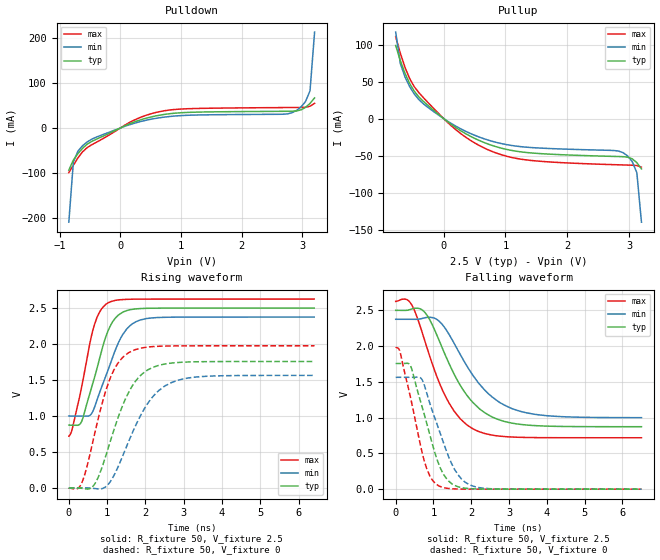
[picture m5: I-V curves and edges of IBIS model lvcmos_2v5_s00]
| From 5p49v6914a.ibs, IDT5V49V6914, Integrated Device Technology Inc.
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|   Model LVCMOS_2V5
[Model]   lvcmos_2v5_s00
Model_type   Output
Polarity   Non-Inverting
|   typ   min   max
C_comp   2pF   1.5pF   2.5pF
Vmeas = 1.25V
Rref = 50
Cref = 0
Vref = 1.25V
|   typ   min   max
[Voltage range]   2.5V   2.375V   2.625V
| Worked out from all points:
|   slope of the pulldown table from 0 to 0.375 V, typ, clamps not added: 18.9 ohm
|   slope of the pullup table from 0 to 0.375 V, typ, clamps not added: 17.6 ohm
|   rising waveform, R_fixture 50, V_fixture 2.5: 20-80 % time 531ps typ, 605ps min, 446ps max; typ from 0.873 V to 2.5 V
|   falling waveform, R_fixture 50, V_fixture 2.5: 20-80 % time 998ps typ, 1.11ns min, 867ps max; typ from 2.5 V to 0.873 V
|   rising waveform, R_fixture 50, V_fixture 0: 20-80 % time 736ps typ, 865ps min, 606ps max; typ from 0 V to 1.76 V
|   falling waveform, R_fixture 50, V_fixture 0: 20-80 % time 579ps typ, 649ps min, 498ps max; typ from 1.76 V to 0 V
[Pulldown]
|Voltage   I (typ)   I (min)   I (max)
|Note, modeling breaks down at 250mA and above.  This is well beyond the functional   |
|operating range of the device.  Should this scenario occur, catastrophic failure and   |
|possible damage to the device and/or board is of higher concern than the I-V curve   |
|behavior.  The IBIS checker will flag currents in excess of 10A with warnings.  Lines   |
|with currents in excess of 0.35 A have been commented out.  The points still remain|
|available to the user if the user desires to use them.   |
|-2.50000e+00   -2.65608e+02   -2.29941e+02   -3.26165e+02
|-2.42500e+00   -2.52343e+02   -2.18875e+02   -3.09252e+02
|-2.35000e+00   -2.39080e+02   -2.07811e+02   -2.92340e+02
|-2.27500e+00   -2.25818e+02   -1.96747e+02   -2.75428e+02
|-2.20000e+00   -2.12557e+02   -1.85685e+02   -2.58518e+02
|-2.12500e+00   -1.99297e+02   -1.74624e+02   -2.41608e+02
|-2.05000e+00   -1.86039e+02   -1.63565e+02   -2.24700e+02
|-1.97500e+00   -1.72782e+02   -1.52508e+02   -2.07793e+02
|-1.90000e+00   -1.59528e+02   -1.41453e+02   -1.90888e+02
|-1.82500e+00   -1.46276e+02   -1.30401e+02   -1.73985e+02
|-1.75000e+00   -1.33027e+02   -1.19352e+02   -1.57085e+02
|-1.67500e+00   -1.19782e+02   -1.08307e+02   -1.40188e+02
|-1.60000e+00   -1.06542e+02   -9.72682e+01   -1.23295e+02
|-1.52500e+00   -9.33090e+01   -8.62359e+01   -1.06409e+02
|-1.45000e+00   -8.00850e+01   -7.52129e+01   -8.95309e+01
|-1.37500e+00   -6.68743e+01   -6.42029e+01   -7.26657e+01
|-1.30000e+00   -5.36897e+01   -5.32178e+01   -5.58258e+01
|-1.22500e+00   -4.05463e+01   -4.22664e+01   -3.90371e+01
|-1.15000e+00   -2.74527e+01   -3.13543e+01   -2.23159e+01
|-1.07500e+00   -1.44175e+01   -2.04874e+01   -5.67477e+00
|-1.00000e+00   -2.41445e+00   -9.65733e+00   -2.99544e-01
|-9.25000e-01   -2.45532e-01   -1.42571e+00   -1.20411e-01
-850mV    -93.99mA   -210mA     -99.45mA
-775mV    -71.55mA   -76.14mA   -83.12mA
-700mV    -57.23mA   -51.66mA   -66.79mA
-550mV    -36.49mA   -31.4mA    -44.03mA
200mV     11.86mA    9.308mA    15.7mA
650mV     28.48mA    22.79mA    36.43mA
1.175V    34.92mA    28.53mA    43.11mA
2.825V    37.25mA    33.68mA    45.54mA
2.975V    40.25mA    46.76mA    45.71mA
3.05V     45.87mA    58.57mA    46.09mA
3.125V    54.76mA    82.96mA    48.46mA
3.2V      67.01mA    213.6mA    54.81mA
| 3.27500e+00   8.22893e-02   1.48202e+00   6.52461e-02
| 3.35000e+00   1.11691e-01   1.21021e+01   7.95740e-02
| 3.42500e+00   4.17187e-01   2.91692e+01   9.49987e-02
| 3.50000e+00   5.44922e+00   4.62676e+01   1.08609e-01
| 3.57500e+00   2.52763e+01   6.34104e+01   1.52479e-01
| 3.65000e+00   4.58138e+01   8.05959e+01   1.32846e+00
| 3.72500e+00   6.64097e+01   9.78129e+01   2.01980e+01
| 3.80000e+00   8.70553e+01   1.15052e+02   4.64595e+01
| 3.87500e+00   1.07734e+02   1.32307e+02   7.28003e+01
| 3.95000e+00   1.28434e+02   1.49572e+02   9.91974e+01
| 4.02500e+00   1.49148e+02   1.66846e+02   1.25626e+02
| 4.10000e+00   1.69871e+02   1.84125e+02   1.52073e+02
| 4.17500e+00   1.90602e+02   2.01410e+02   1.78532e+02
| 4.25000e+00   2.11338e+02   2.18698e+02   2.05000e+02
| 4.32500e+00   2.32079e+02   2.35990e+02   2.31473e+02
| 4.40000e+00   2.52823e+02   2.53284e+02   2.57951e+02
| 4.47500e+00   2.73570e+02   2.70581e+02   2.84433e+02
| 4.55000e+00   2.94320e+02   2.87880e+02   3.10918e+02
| 4.62500e+00   3.15072e+02   3.05181e+02   3.37405e+02
| 4.70000e+00   3.35826e+02   3.22484e+02   3.63895e+02
| 4.77500e+00   3.56582e+02   3.39789e+02   3.90387e+02
| 4.85000e+00   3.77340e+02   3.57095e+02   4.16881e+02
| 4.92500e+00   3.98099e+02   3.74402e+02   4.43377e+02
| 5.00000e+00   4.18860e+02   3.91711e+02   4.69874e+02
[Pullup]
|Voltage   I (typ)   I (min)   I (max)
|Note, modeling breaks down at 250mA and above.  This is well beyond the functional   |
|operating range of the device.  Should this scenario occur, catastrophic failure and   |
|possible damage to the device and/or board is of higher concern than the I-V curve   |
|behavior.  The IBIS checker will flag currents in excess of 10A with warnings.  Lines   |
|with currents in excess of 0.35 A have been commented out.  The points still remain|
|available to the user if the user desires to use them.   |
|-2.50000e+00   4.18924e+02   3.62922e+02   5.14110e+02
|-2.42500e+00   3.98163e+02   3.45615e+02   4.87611e+02
|-2.35000e+00   3.77403e+02   3.28309e+02   4.61112e+02
|-2.27500e+00   3.56644e+02   3.11005e+02   4.34615e+02
|-2.20000e+00   3.35887e+02   2.93702e+02   4.08119e+02
|-2.12500e+00   3.15132e+02   2.76401e+02   3.81625e+02
|-2.05000e+00   2.94379e+02   2.59102e+02   3.55132e+02
|-1.97500e+00   2.73627e+02   2.41805e+02   3.28642e+02
|-1.90000e+00   2.52879e+02   2.24511e+02   3.02154e+02
|-1.82500e+00   2.32133e+02   2.07220e+02   2.75668e+02
|-1.75000e+00   2.11391e+02   1.89933e+02   2.49186e+02
|-1.67500e+00   1.90653e+02   1.72650e+02   2.22708e+02
|-1.60000e+00   1.69920e+02   1.55373e+02   1.96234e+02
|-1.52500e+00   1.49194e+02   1.38102e+02   1.69767e+02
|-1.45000e+00   1.28478e+02   1.20842e+02   1.43309e+02
|-1.37500e+00   1.07776e+02   1.03595e+02   1.16864e+02
|-1.30000e+00   8.70950e+01   8.63670e+01   9.04416e+01
|-1.22500e+00   6.64470e+01   6.91675e+01   6.40570e+01
|-1.15000e+00   4.58485e+01   5.20071e+01   3.77381e+01
|-1.07500e+00   2.53080e+01   3.48921e+01   1.14975e+01
|-1.00000e+00   5.47770e+00   1.78138e+01   5.20511e-01
|-9.25000e-01   4.42241e-01   3.17254e+00   1.56153e-01
|-8.50000e-01   1.32908e-01   3.92497e-01   1.29698e-01
-775mV    98.68mA    116.8mA    110.3mA
-700mV    78.11mA    74.31mA    88.11mA
-625mV    61.11mA    56.31mA    69.18mA
-475mV    36.93mA    33.22mA    43.05mA
-325mV    23.07mA    19.8mA     28.08mA
125mV     -7.951mA   -6.687mA   -9.848mA
575mV     -29.56mA   -24.95mA   -36.3mA
1.325V    -45.7mA    -38.54mA   -55.7mA
2.9V      -51.46mA   -45.91mA   -62.61mA
3.05V     -54.28mA   -57.96mA   -62.98mA
3.125V    -59.49mA   -72.96mA   -63.43mA
3.2V      -67.99mA   -139.9mA   -65.6mA
| 3.27500e+00   -7.95179e-02   -7.11252e-01   -7.19088e-02
| 3.35000e+00   -9.96915e-02   -6.05603e+00   -8.27613e-02
| 3.42500e+00   -2.49209e-01   -1.68766e+01   -9.65190e-02
| 3.50000e+00   -2.41654e+00   -2.77285e+01   -1.10622e-01
| 3.57500e+00   -1.44189e+01   -3.86247e+01   -1.40364e-01
| 3.65000e+00   -2.74535e+01   -4.95634e+01   -6.78328e-01
| 3.72500e+00   -4.05466e+01   -6.05360e+01   -1.12141e+01
| 3.80000e+00   -5.36896e+01   -7.15395e+01   -2.78806e+01
| 3.87500e+00   -6.68736e+01   -8.25581e+01   -4.46279e+01
| 3.95000e+00   -8.00835e+01   -9.35871e+01   -6.14343e+01
| 4.02500e+00   -9.33072e+01   -1.04624e+02   -7.82862e+01
| 4.10000e+00   -1.06540e+02   -1.15666e+02   -9.51560e+01
| 4.17500e+00   -1.19780e+02   -1.26714e+02   -1.12037e+02
| 4.25000e+00   -1.33024e+02   -1.37764e+02   -1.28926e+02
| 4.32500e+00   -1.46273e+02   -1.48818e+02   -1.45820e+02
| 4.40000e+00   -1.59525e+02   -1.59874e+02   -1.62718e+02
| 4.47500e+00   -1.72779e+02   -1.70933e+02   -1.79619e+02
| 4.55000e+00   -1.86036e+02   -1.81993e+02   -1.96523e+02
| 4.62500e+00   -1.99294e+02   -1.93055e+02   -2.13429e+02
| 4.70000e+00   -2.12554e+02   -2.04118e+02   -2.30337e+02
| 4.77500e+00   -2.25816e+02   -2.15182e+02   -2.47246e+02
| 4.85000e+00   -2.39078e+02   -2.26248e+02   -2.64156e+02
| 4.92500e+00   -2.52342e+02   -2.37314e+02   -2.81068e+02
| 5.00000e+00   -2.65606e+02   -2.48382e+02   -2.97980e+02
[Ramp]
|   typ   min   max
dV/dt_r   1.063/0.739n   0.946/0.869n   1.195/0.609n
dV/dt_f   0.994/1.005n   0.841/1.117n   1.163/0.875n
R_load =   50
[Rising Waveform]
R_fixture = 50
V_fixture = 2.5   |Vcc_typ
V_fixture_min = 2.375 |Vcc_min
V_fixture_max = 2.625 |Vcc_max
C_fixture = 0.0p
| Time   typ   min   max
| 0.00000e+00   8.73021e-01   9.99328e-01   7.18803e-01
| 2.82958e-12   8.73021e-01   9.99328e-01   7.18803e-01
| 5.01945e-12   8.73021e-01   9.99328e-01   7.18803e-01
| 5.29250e-12   8.73021e-01   9.99328e-01   7.18803e-01
| 8.83938e-12   8.73021e-01   9.99328e-01   7.18803e-01
| 1.58159e-11   8.73021e-01   9.99328e-01   7.18803e-01
| 1.65816e-11   8.73021e-01   9.99328e-01   7.18803e-01
| 3.09307e-11   8.73021e-01   9.99328e-01   7.18803e-01
| 4.33456e-11   8.73021e-01   9.99328e-01   7.18803e-01
| 4.84997e-11   8.73021e-01   9.99328e-01   7.18803e-01
| 5.92498e-11   8.73021e-01   9.99328e-01   7.18803e-01
| 6.33903e-11   8.73021e-01   9.99328e-01   7.18803e-01
| 7.24942e-11   8.73021e-01   9.99328e-01   7.18803e-01
| 7.37142e-11   8.73021e-01   9.99328e-01   7.18803e-01
| 7.72112e-11   8.73021e-01   9.99328e-01   7.18803e-01
| 8.08094e-11   8.73021e-01   9.99328e-01   7.18803e-01
| 8.33740e-11   8.73021e-01   9.99328e-01   7.18803e-01
| 8.93880e-11   8.73021e-01   9.99328e-01   7.18803e-01
| 1.00166e-10   8.73021e-01   9.99328e-01   7.18804e-01
| 1.04900e-10   8.73021e-01   9.99328e-01   7.18804e-01
| 1.14234e-10   8.73022e-01   9.99328e-01   7.18804e-01
| 1.18465e-10   8.73022e-01   9.99329e-01   7.18804e-01
| 1.25023e-10   8.73022e-01   9.99329e-01   7.18804e-01
| 1.37358e-10   8.73022e-01   9.99329e-01   7.18804e-01
| 1.40589e-10   8.73022e-01   9.99329e-01   7.18804e-01
| 1.51767e-10   8.73021e-01   9.99328e-01   7.18802e-01
| 1.61060e-10   8.73019e-01   9.99327e-01   7.18800e-01
| 1.69091e-10   8.73016e-01   9.99324e-01   7.18798e-01
| 1.80923e-10   8.73012e-01   9.99320e-01   7.18792e-01
| 1.98540e-10   8.73004e-01   9.99312e-01   7.18784e-01
| 2.03752e-10   8.73002e-01   9.99309e-01   7.18782e-01
| 2.22970e-10   8.72994e-01   9.99302e-01   7.18775e-01
| 2.39229e-10   8.72989e-01   9.99298e-01   7.18772e-01
| 2.45359e-10   8.72988e-01   9.99296e-01   7.18773e-01
| 2.53236e-10   8.72988e-01   9.99294e-01   7.18776e-01
| 2.61834e-10   8.72990e-01   9.99294e-01   7.18782e-01
| 2.68845e-10   8.72994e-01   9.99295e-01   7.18785e-01
| 2.75097e-10   8.72996e-01   9.99297e-01   7.18788e-01
| 2.84408e-10   8.73000e-01   9.99300e-01   7.18791e-01
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0s        873mV      999.3mV    718.8mV
82.27ps   872.4mV    998.8mV    805.2mV
342.9ps   934.1mV    998.5mV    1.423V
544.2ps   1.3V       1.006V     1.997V
666.1ps   1.523V     1.114V     2.265V
845.8ps   1.89V      1.387V     2.481V
1.024ns   2.183V     1.637V     2.572V
1.422ns   2.447V     2.143V     2.619V
1.873ns   2.493V     2.336V     2.624V
6.407ns   2.5V       2.375V     2.625V
[Falling Waveform]
R_fixture = 50
V_fixture = 2.5   |Vcc_typ
V_fixture_min = 2.375 |Vcc_min
V_fixture_max = 2.625 |Vcc_max
C_fixture = 0.0p
| Time   typ   min   max
| 0.00000e+00   2.50000e+00   2.37500e+00   2.62500e+00
| 2.82958e-12   2.50000e+00   2.37500e+00   2.62500e+00
| 5.01945e-12   2.50000e+00   2.37500e+00   2.62500e+00
| 5.29250e-12   2.50000e+00   2.37500e+00   2.62500e+00
| 8.83938e-12   2.50000e+00   2.37500e+00   2.62500e+00
| 1.58159e-11   2.50000e+00   2.37500e+00   2.62500e+00
| 1.65816e-11   2.50000e+00   2.37500e+00   2.62500e+00
| 3.09306e-11   2.50000e+00   2.37500e+00   2.62500e+00
| 4.33456e-11   2.50000e+00   2.37500e+00   2.62500e+00
| 4.84997e-11   2.50000e+00   2.37500e+00   2.62500e+00
| 5.92499e-11   2.50000e+00   2.37500e+00   2.62500e+00
| 6.33904e-11   2.50000e+00   2.37500e+00   2.62500e+00
| 7.24942e-11   2.50000e+00   2.37500e+00   2.62500e+00
| 7.37143e-11   2.50000e+00   2.37500e+00   2.62500e+00
| 7.72112e-11   2.50000e+00   2.37500e+00   2.62500e+00
| 8.08094e-11   2.50000e+00   2.37500e+00   2.62500e+00
| 8.33740e-11   2.50000e+00   2.37500e+00   2.62500e+00
| 8.93881e-11   2.50000e+00   2.37500e+00   2.62500e+00
| 1.00162e-10   2.50000e+00   2.37500e+00   2.62500e+00
| 1.04901e-10   2.50000e+00   2.37500e+00   2.62500e+00
| 1.14235e-10   2.50000e+00   2.37500e+00   2.62500e+00
| 1.18460e-10   2.50000e+00   2.37500e+00   2.62500e+00
| 1.25023e-10   2.50000e+00   2.37500e+00   2.62500e+00
| 1.37358e-10   2.50000e+00   2.37500e+00   2.62500e+00
| 1.40585e-10   2.50000e+00   2.37500e+00   2.62500e+00
| 1.51766e-10   2.50000e+00   2.37500e+00   2.62500e+00
| 1.61057e-10   2.50000e+00   2.37500e+00   2.62500e+00
| 1.69080e-10   2.50000e+00   2.37500e+00   2.62500e+00
| 1.80919e-10   2.49999e+00   2.37500e+00   2.62499e+00
| 1.99499e-10   2.49999e+00   2.37499e+00   2.62499e+00
| 2.05003e-10   2.49999e+00   2.37499e+00   2.62499e+00
| 2.24273e-10   2.49998e+00   2.37498e+00   2.62498e+00
| 2.39981e-10   2.49998e+00   2.37498e+00   2.62498e+00
| 2.47898e-10   2.49998e+00   2.37498e+00   2.62498e+00
| 2.62665e-10   2.49998e+00   2.37498e+00   2.62499e+00
| 2.73527e-10   2.49998e+00   2.37498e+00   2.62499e+00
| 2.79768e-10   2.49998e+00   2.37498e+00   2.62499e+00
| 2.89155e-10   2.49999e+00   2.37498e+00   2.62500e+00
| 2.95491e-10   2.49999e+00   2.37498e+00   2.62500e+00
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0s        2.5V       2.375V     2.625V
395.8ps   2.514V     2.375V     2.6V
795.8ps   2.456V     2.399V     2.032V
1.089ns   2.156V     2.373V     1.576V
1.36ns    1.819V     2.21V      1.255V
1.71ns    1.452V     1.882V     983.5mV
2.042ns   1.213V     1.592V     844.6mV
2.67ns    983.2mV    1.243V     746.4mV
3.397ns   900.4mV    1.075V     723.5mV
6.508ns   873.1mV    999.8mV    718.8mV
[Rising Waveform]
R_fixture = 50
V_fixture = 0
C_fixture = 0.0p
| Time   typ   min   max
| 0.00000e+00   6.87937e-09   4.94005e-08   5.62352e-09
| 2.82958e-12   9.39157e-09   5.18209e-08   8.20033e-09
| 5.01945e-12   1.05581e-08   5.29931e-08   9.33987e-09
| 5.29250e-12   1.06628e-08   5.30634e-08   9.47845e-09
| 8.83938e-12   1.14816e-08   5.39073e-08   1.01769e-08
| 1.58159e-11   9.81130e-09   5.35175e-08   7.82962e-09
| 1.65816e-11   9.85627e-09   5.39615e-08   7.55894e-09
| 3.09307e-11   1.50764e-08   6.38826e-08   9.11087e-09
| 4.33456e-11   5.21545e-08   9.87199e-08   4.07320e-08
| 4.84997e-11   6.75477e-08   1.14275e-07   5.79639e-08
| 5.92498e-11   1.01130e-07   1.49632e-07   9.24943e-08
| 6.33903e-11   1.01692e-07   1.48315e-07   1.03972e-07
| 7.24942e-11   7.31924e-08   1.02828e-07   9.86609e-08
| 7.37142e-11   5.88126e-08   7.73980e-08   9.03629e-08
| 7.72112e-11   -3.95219e-09   4.51221e-09   5.75014e-08
| 8.08094e-11   -7.54585e-08   -9.72558e-08   1.82286e-08
| 8.33740e-11   -1.30114e-07   -1.50261e-07   1.63174e-08
| 8.93880e-11   -1.48483e-07   -2.64533e-07   4.55777e-08
| 1.00166e-10   1.24715e-07   -4.27491e-08   3.34632e-07
| 1.04900e-10   3.02299e-07   1.49095e-07   5.73652e-07
| 1.14234e-10   9.38485e-07   7.75461e-07   9.82572e-07
| 1.18465e-10   1.16758e-06   1.08592e-06   1.13983e-06
| 1.25023e-10   1.50679e-06   1.56707e-06   1.16138e-06
| 1.37358e-10   1.64374e-06   1.93927e-06   9.99399e-07
| 1.40589e-10   1.48316e-06   1.94748e-06   9.02992e-07
| 1.51767e-10   5.02520e-07   1.34338e-06   -1.50975e-07
| 1.61060e-10   -1.03282e-06   -4.02985e-07   -2.43195e-06
| 1.69091e-10   -3.75918e-06   -2.59629e-06   -4.52065e-06
| 1.80923e-10   -7.88718e-06   -6.71275e-06   -9.21064e-06
| 1.98540e-10   -1.48427e-05   -1.37498e-05   -1.59177e-05
| 2.03752e-10   -1.65377e-05   -1.57906e-05   -1.78603e-05
| 2.22970e-10   -2.24928e-05   -2.19505e-05   -2.34608e-05
| 2.39229e-10   -2.68321e-05   -2.61824e-05   -2.48124e-05
| 2.45360e-10   -2.73651e-05   -2.77472e-05   -2.41019e-05
| 2.53236e-10   -2.75026e-05   -2.88967e-05   -2.07341e-05
| 2.61834e-10   -2.50357e-05   -2.91170e-05   -1.50696e-05
| 2.68845e-10   -2.15683e-05   -2.81518e-05   -1.16260e-05
| 2.75097e-10   -1.87100e-05   -2.59378e-05   -8.92132e-06
| 2.84408e-10   -1.47909e-05   -2.25686e-05   -6.60182e-06
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0s        6.879nV    49.4nV     5.624nV
326.9ps   -4.667mV   42.68uV    58.16mV
451ps     -13.96mV   247.1uV    251.9mV
697.3ps   72.84mV    -9.194mV   804.8mV
1.091ns   660.8mV    93.36mV    1.538V
1.555ns   1.32V      637.5mV    1.878V
1.804ns   1.525V     934.4mV    1.932V
2.135ns   1.66V      1.23V      1.962V
2.805ns   1.742V     1.49V      1.974V
6.417ns   1.757V     1.564V     1.975V
[Falling Waveform]
R_fixture = 50
V_fixture = 0
C_fixture = 0.0p
| Time   typ   min   max
| 0.00000e+00   1.75700e+00   1.56389e+00   1.97545e+00
| 1.99499e-10   1.75699e+00   1.56388e+00   1.97544e+00
| 2.24273e-10   1.75698e+00   1.56387e+00   1.97543e+00
| 2.63808e-10   1.75697e+00   1.56386e+00   1.97543e+00
| 3.01812e-10   1.75699e+00   1.56387e+00   1.97544e+00
| 3.86470e-10   1.75699e+00   1.56388e+00   1.97545e+00
| 4.27401e-10   1.75700e+00   1.56389e+00   1.97545e+00
| 7.14375e-10   1.75700e+00   1.56390e+00   1.97546e+00
| 7.53456e-10   1.75700e+00   1.56389e+00   1.97545e+00
| 8.44628e-10   1.75700e+00   1.56390e+00   1.97544e+00
| 9.56627e-10   1.75699e+00   1.56390e+00   1.97546e+00
| 9.95333e-10   1.75699e+00   1.56389e+00   1.97547e+00
| 1.07228e-09   1.75700e+00   1.56389e+00   1.97546e+00
| 1.12623e-09   1.75701e+00   1.56388e+00   1.97545e+00
| 1.18162e-09   1.75701e+00   1.56389e+00   1.97546e+00
| 1.29679e-09   1.75701e+00   1.56390e+00   1.97546e+00
| 1.37555e-09   1.75701e+00   1.56391e+00   1.97540e+00
| 1.41895e-09   1.75702e+00   1.56391e+00   1.97544e+00
| 1.42811e-09   1.75702e+00   1.56391e+00   1.97552e+00
| 1.44671e-09   1.75702e+00   1.56391e+00   1.97573e+00
| 1.46338e-09   1.75702e+00   1.56390e+00   1.97610e+00
| 1.47276e-09   1.75702e+00   1.56390e+00   1.97648e+00
| 1.48171e-09   1.75702e+00   1.56390e+00   1.97697e+00
| 1.49743e-09   1.75702e+00   1.56390e+00   1.97793e+00
| 1.51410e-09   1.75702e+00   1.56390e+00   1.97845e+00
| 1.51950e-09   1.75702e+00   1.56390e+00   1.97831e+00
| 1.53374e-09   1.75702e+00   1.56390e+00   1.97724e+00
| 1.55213e-09   1.75702e+00   1.56391e+00   1.97282e+00
| 1.56326e-09   1.75701e+00   1.56391e+00   1.96771e+00
| 1.57738e-09   1.75700e+00   1.56391e+00   1.95713e+00
| 1.59292e-09   1.75700e+00   1.56391e+00   1.93956e+00
| 1.61891e-09   1.75696e+00   1.56391e+00   1.89448e+00
| 1.63285e-09   1.75695e+00   1.56392e+00   1.86313e+00
| 1.64656e-09   1.75694e+00   1.56392e+00   1.83057e+00
| 1.66868e-09   1.75698e+00   1.56392e+00   1.77586e+00
| 1.68649e-09   1.75707e+00   1.56392e+00   1.73119e+00
| 1.69224e-09   1.75710e+00   1.56392e+00   1.71706e+00
| 1.70422e-09   1.75723e+00   1.56393e+00   1.68774e+00
| 1.71967e-09   1.75747e+00   1.56393e+00   1.65142e+00
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0s        1.757V     1.564V     1.975V
127.2ps   1.757V     1.564V     1.894V
391.3ps   1.726V     1.564V     1.284V
673.6ps   1.198V     1.549V     572.5mV
824.6ps   915.2mV    1.339V     281.6mV
1.139ns   352.6mV    840.8mV    47.09mV
1.354ns   143.2mV    519.5mV    12.94mV
1.564ns   51.38mV    271.5mV    3.901mV
2.032ns   5.223mV    45.24mV    235.9uV
6.508ns   -2.166uV   -2.579uV   -1.571uV
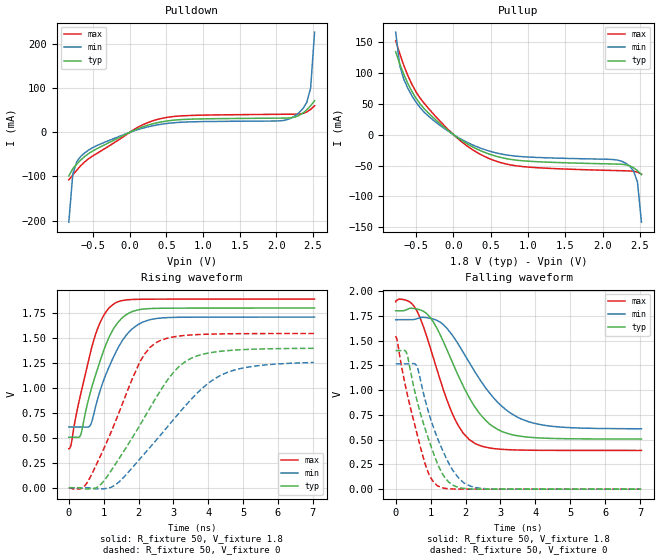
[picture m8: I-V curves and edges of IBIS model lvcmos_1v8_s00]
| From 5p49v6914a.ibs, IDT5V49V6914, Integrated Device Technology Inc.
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|   Model LVCMOS_1V8
[Model]   lvcmos_1v8_s00
Model_type   Output
Polarity   Non-Inverting
|   typ   min   max
C_comp   2pF   1.5pF   2.5pF
Vmeas = 0.9V
Rref = 50
Cref = 0
Vref = 0.9V
|   typ   min   max
[Voltage range]   1.8V   1.71V   1.89V
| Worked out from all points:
|   slope of the pulldown table from 0 to 0.27 V, typ, clamps not added: 15.4 ohm
|   slope of the pullup table from 0 to 0.27 V, typ, clamps not added: 13.1 ohm
|   rising waveform, R_fixture 50, V_fixture 1.8: 20-80 % time 719ps typ, 787ps min, 632ps max; typ from 0.506 V to 1.8 V
|   falling waveform, R_fixture 50, V_fixture 1.8: 20-80 % time 1.1ns typ, 1.32ns min, 875ps max; typ from 1.8 V to 0.506 V
|   rising waveform, R_fixture 50, V_fixture 0: 20-80 % time 1.5ns typ, 1.91ns min, 1.11ns max; typ from 0 V to 1.4 V
|   falling waveform, R_fixture 50, V_fixture 0: 20-80 % time 708ps typ, 767ps min, 628ps max; typ from 1.4 V to 0 V
[Pulldown]
|Voltage   I (typ)   I (min)   I (max)
|Note, modeling breaks down at 250mA and above.  This is well beyond the functional   |
|operating range of the device.  Should this scenario occur, catastrophic failure and   |
|possible damage to the device and/or board is of higher concern than the I-V curve   |
|behavior.  The IBIS checker will flag currents in excess of 10A with warnings.  Lines   |
|with currents in excess of 0.35 A have been commented out.  The points still remain|
|available to the user if the user desires to use them.   |
|-1.80000e+00   -1.57123e+02   -1.41687e+02   -1.84032e+02
|-1.74600e+00   -1.46350e+02   -1.32525e+02   -1.70600e+02
|-1.69200e+00   -1.35593e+02   -1.23381e+02   -1.57181e+02
|-1.63800e+00   -1.24855e+02   -1.14259e+02   -1.43777e+02
|-1.58400e+00   -1.14140e+02   -1.05164e+02   -1.30391e+02
|-1.53000e+00   -1.03454e+02   -9.61014e+01   -1.17030e+02
|-1.47600e+00   -9.28051e+01   -8.70803e+01   -1.03700e+02
|-1.42200e+00   -8.22059e+01   -7.81126e+01   -9.04125e+01
|-1.36800e+00   -7.16734e+01   -6.92147e+01   -7.71843e+01
|-1.31400e+00   -6.12369e+01   -6.04138e+01   -6.40446e+01
|-1.26000e+00   -5.09378e+01   -5.17410e+01   -5.10499e+01
|-1.20600e+00   -4.08235e+01   -4.32303e+01   -3.82636e+01
|-1.15200e+00   -3.09387e+01   -3.49134e+01   -2.57664e+01
|-1.09800e+00   -2.12858e+01   -2.67907e+01   -1.35591e+01
|-1.04400e+00   -1.18008e+01   -1.88242e+01   -2.48786e+00
|-9.90000e-01   -2.94592e+00   -1.09564e+01   -3.30913e-01
|-9.36000e-01   -5.04093e-01   -3.41190e+00   -1.45436e-01
|-8.82000e-01   -1.55884e-01   -7.28672e-01   -1.19691e-01
-828mV    -98.74mA   -203.8mA   -107.8mA
-774mV    -82.54mA   -94.98mA   -96.94mA
-720mV    -71.89mA   -66.58mA   -85.84mA
-612mV    -54.71mA   -46.44mA   -66.79mA
-450mV    -37.4mA    -30.21mA   -48.14mA
144mV     10.52mA    8.041mA    14.45mA
468mV     24.92mA    19.47mA    32.9mA
2.034V    32.4mA     26.18mA    41.13mA
2.304V    38.17mA    44.17mA    41.74mA
2.412V    50.97mA    67.63mA    46.33mA
2.466V    60.46mA    100.4mA    52.18mA
2.52V     72.02mA    227.8mA    60.53mA
| 2.57400e+00   8.57382e-02   8.78094e-01   7.13755e-02
| 2.62800e+00   1.08415e-01   4.40618e+00   8.43612e-02
| 2.68200e+00   2.11755e-01   1.54961e+01   9.74736e-02
| 2.73600e+00   9.45213e-01   2.77829e+01   1.08890e-01
| 2.79000e+00   6.44762e+00   4.00829e+01   1.24073e-01
| 2.84400e+00   2.08796e+01   5.24028e+01   1.97645e-01
| 2.89800e+00   3.56490e+01   6.47465e+01   1.06236e+00
| 2.95200e+00   5.04441e+01   7.71133e+01   1.09978e+01
| 3.00600e+00   6.52701e+01   8.94994e+01   2.98762e+01
| 3.06000e+00   8.01244e+01   1.01900e+02   4.87902e+01
| 3.11400e+00   9.50001e+01   1.14313e+02   6.77471e+01
| 3.16800e+00   1.09892e+02   1.26734e+02   8.67385e+01
| 3.22200e+00   1.24795e+02   1.39162e+02   1.05753e+02
| 3.27600e+00   1.39706e+02   1.51595e+02   1.24783e+02
| 3.33000e+00   1.54624e+02   1.64032e+02   1.43824e+02
| 3.38400e+00   1.69547e+02   1.76473e+02   1.62872e+02
| 3.43800e+00   1.84473e+02   1.88917e+02   1.81926e+02
| 3.49200e+00   1.99403e+02   2.01364e+02   2.00984e+02
| 3.54600e+00   2.14336e+02   2.13813e+02   2.20045e+02
| 3.60000e+00   2.29271e+02   2.26263e+02   2.39110e+02
[Pullup]
|Voltage   I (typ)   I (min)   I (max)
|Note, modeling breaks down at 250mA and above.  This is well beyond the functional   |
|operating range of the device.  Should this scenario occur, catastrophic failure and   |
|possible damage to the device and/or board is of higher concern than the I-V curve   |
|behavior.  The IBIS checker will flag currents in excess of 10A with warnings.  Lines   |
|with currents in excess of 0.35 A have been commented out.  The points still remain|
|available to the user if the user desires to use them.   |
|-1.80000e+00   2.29375e+02   2.05604e+02   2.71011e+02
|-1.74600e+00   2.14438e+02   1.93155e+02   2.51941e+02
|-1.69200e+00   1.99503e+02   1.80708e+02   2.32873e+02
|-1.63800e+00   1.84571e+02   1.68264e+02   2.13807e+02
|-1.58400e+00   1.69642e+02   1.55823e+02   1.94744e+02
|-1.53000e+00   1.54718e+02   1.43387e+02   1.75685e+02
|-1.47600e+00   1.39798e+02   1.30955e+02   1.56630e+02
|-1.42200e+00   1.24884e+02   1.18529e+02   1.37582e+02
|-1.36800e+00   1.09978e+02   1.06112e+02   1.18541e+02
|-1.31400e+00   9.50841e+01   9.37042e+01   9.95128e+01
|-1.26000e+00   8.02054e+01   8.13103e+01   8.05016e+01
|-1.20600e+00   6.53483e+01   6.89341e+01   6.15174e+01
|-1.15200e+00   5.05195e+01   5.65798e+01   4.25710e+01
|-1.09800e+00   3.57213e+01   4.42495e+01   2.36670e+01
|-1.04400e+00   2.09487e+01   3.19407e+01   5.48601e+00
|-9.90000e-01   6.51330e+00   1.96473e+01   6.02004e-01
|-9.36000e-01   1.00727e+00   7.47441e+00   2.29344e-01
|-8.82000e-01   2.69913e-01   1.53012e+00   1.87713e-01
|-8.28000e-01   1.62186e-01   3.86408e-01   1.69987e-01
-774mV    134.2mA    165.8mA    151.8mA
-720mV    114.6mA    111.9mA    131.2mA
-666mV    97.64mA    89.72mA    112.2mA
-504mV    59.35mA    52.84mA    69.59mA
-342mV    35.66mA    30.61mA    43.41mA
-18mV     1.676mA    1.404mA    2.092mA
360mV     -25.81mA   -21.74mA   -31.86mA
900mV     -42.04mA   -35.5mA    -51.35mA
2.304V    -48.62mA   -45.83mA   -58.53mA
2.412V    -53.4mA    -58.27mA   -59.21mA
2.466V    -58.21mA   -76.35mA   -60.65mA
2.52V     -64.73mA   -141.7mA   -64.05mA
| 2.57400e+00   -7.32856e-02   -4.47707e-01   -6.97922e-02
| 2.62800e+00   -8.79644e-02   -2.00025e+00   -7.77007e-02
| 2.68200e+00   -1.43736e-01   -8.33672e+00   -8.69778e-02
| 2.73600e+00   -4.90693e-01   -1.61824e+01   -9.65121e-02
| 2.79000e+00   -2.93152e+00   -2.41086e+01   -1.08871e-01
| 2.84400e+00   -1.17857e+01   -3.21721e+01   -1.52056e-01
| 2.89800e+00   -2.12700e+01   -4.04227e+01   -5.63058e-01
| 2.95200e+00   -3.09224e+01   -4.88696e+01   -5.50618e+00
| 3.00600e+00   -4.08067e+01   -5.74918e+01   -1.75817e+01
| 3.06000e+00   -5.09214e+01   -6.62527e+01   -2.98766e+01
| 3.11400e+00   -6.12182e+01   -7.51218e+01   -4.24771e+01
| 3.16800e+00   -7.16546e+01   -8.40680e+01   -5.53423e+01
| 3.22200e+00   -8.21870e+01   -9.30724e+01   -6.83916e+01
| 3.27600e+00   -9.27859e+01   -1.02122e+02   -8.15645e+01
| 3.33000e+00   -1.03434e+02   -1.11207e+02   -9.48151e+01
| 3.38400e+00   -1.14120e+02   -1.20320e+02   -1.08118e+02
| 3.43800e+00   -1.24835e+02   -1.29457e+02   -1.21460e+02
| 3.49200e+00   -1.35573e+02   -1.38613e+02   -1.34829e+02
| 3.54600e+00   -1.46330e+02   -1.47785e+02   -1.48221e+02
| 3.60000e+00   -1.57103e+02   -1.56971e+02   -1.61631e+02
[Ramp]
|   typ   min   max
dV/dt_r   0.845/1.509n   0.759/1.922n   0.935/1.123n
dV/dt_f   0.791/1.119n   0.674/1.339n   0.916/0.888n
R_load =   50
[Rising Waveform]
R_fixture = 50
V_fixture = 1.8   |Vcc_typ
V_fixture_min = 1.71 |Vcc_min
V_fixture_max = 1.89 |Vcc_max
C_fixture = 0.0p
| Time   typ   min   max
| 0.00000e+00   5.05771e-01   6.08763e-01   3.90768e-01
| 2.47507e-12   5.05771e-01   6.08763e-01   3.90768e-01
| 4.34525e-12   5.05771e-01   6.08763e-01   3.90768e-01
| 4.57959e-12   5.05771e-01   6.08763e-01   3.90768e-01
| 7.76228e-12   5.05771e-01   6.08763e-01   3.90768e-01
| 1.40250e-11   5.05771e-01   6.08763e-01   3.90768e-01
| 1.46859e-11   5.05771e-01   6.08763e-01   3.90768e-01
| 2.75535e-11   5.05771e-01   6.08763e-01   3.90768e-01
| 3.89156e-11   5.05771e-01   6.08763e-01   3.90768e-01
| 4.27651e-11   5.05771e-01   6.08763e-01   3.90768e-01
| 5.19470e-11   5.05771e-01   6.08763e-01   3.90768e-01
| 6.09735e-11   5.05771e-01   6.08763e-01   3.90768e-01
| 6.28654e-11   5.05771e-01   6.08763e-01   3.90768e-01
| 7.18355e-11   5.05771e-01   6.08763e-01   3.90768e-01
| 7.20853e-11   5.05771e-01   6.08763e-01   3.90768e-01
| 7.57553e-11   5.05771e-01   6.08763e-01   3.90768e-01
| 7.80681e-11   5.05771e-01   6.08763e-01   3.90768e-01
| 7.93944e-11   5.05771e-01   6.08763e-01   3.90768e-01
| 8.55418e-11   5.05771e-01   6.08763e-01   3.90768e-01
| 9.55024e-11   5.05771e-01   6.08763e-01   3.90768e-01
| 9.79222e-11   5.05771e-01   6.08763e-01   3.90768e-01
| 1.07935e-10   5.05771e-01   6.08763e-01   3.90768e-01
| 1.13390e-10   5.05771e-01   6.08763e-01   3.90768e-01
| 1.17787e-10   5.05771e-01   6.08763e-01   3.90768e-01
| 1.27331e-10   5.05771e-01   6.08763e-01   3.90768e-01
| 1.31897e-10   5.05771e-01   6.08763e-01   3.90768e-01
| 1.39387e-10   5.05771e-01   6.08763e-01   3.90768e-01
| 1.47497e-10   5.05771e-01   6.08763e-01   3.90768e-01
| 1.52118e-10   5.05771e-01   6.08763e-01   3.90768e-01
| 1.61717e-10   5.05771e-01   6.08763e-01   3.90768e-01
| 1.72749e-10   5.05771e-01   6.08763e-01   3.90768e-01
| 1.76286e-10   5.05771e-01   6.08763e-01   3.90768e-01
| 1.87607e-10   5.05771e-01   6.08763e-01   3.90768e-01
| 1.97419e-10   5.05771e-01   6.08763e-01   3.90768e-01
| 2.04005e-10   5.05771e-01   6.08763e-01   3.90768e-01
| 2.10686e-10   5.05771e-01   6.08763e-01   3.90768e-01
| 2.18675e-10   5.05771e-01   6.08763e-01   3.90768e-01
| 2.24324e-10   5.05771e-01   6.08763e-01   3.90768e-01
| 2.27448e-10   5.05771e-01   6.08763e-01   3.90768e-01
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0s        505.8mV    608.8mV    390.8mV
68.54ps   505.8mV    608.8mV    435mV
337.8ps   528.4mV    608.8mV    934mV
605ps     939mV      618.7mV    1.334V
761ps     1.123V     804mV      1.53V
931.1ps   1.305V     1.008V     1.679V
1.309ns   1.607V     1.329V     1.845V
1.791ns   1.76V      1.584V     1.885V
2.409ns   1.796V     1.689V     1.889V
7.051ns   1.8V       1.71V      1.89V
[Falling Waveform]
R_fixture = 50
V_fixture = 1.8   |Vcc_typ
V_fixture_min = 1.71 |Vcc_min
V_fixture_max = 1.89 |Vcc_max
C_fixture = 0.0p
| Time   typ   min   max
| 0.00000e+00   1.80000e+00   1.71000e+00   1.89000e+00
| 2.47507e-12   1.80000e+00   1.71000e+00   1.89000e+00
| 4.34525e-12   1.80000e+00   1.71000e+00   1.89000e+00
| 4.57959e-12   1.80000e+00   1.71000e+00   1.89000e+00
| 7.76228e-12   1.80000e+00   1.71000e+00   1.89000e+00
| 1.40250e-11   1.80000e+00   1.71000e+00   1.89000e+00
| 1.46859e-11   1.80000e+00   1.71000e+00   1.89000e+00
| 2.75535e-11   1.80000e+00   1.71000e+00   1.89000e+00
| 3.89154e-11   1.80000e+00   1.71000e+00   1.89000e+00
| 4.27652e-11   1.80000e+00   1.71000e+00   1.89000e+00
| 5.19470e-11   1.80000e+00   1.71000e+00   1.89000e+00
| 6.09735e-11   1.80000e+00   1.71000e+00   1.89000e+00
| 6.28654e-11   1.80000e+00   1.71000e+00   1.89000e+00
| 7.18355e-11   1.80000e+00   1.71000e+00   1.89000e+00
| 7.20853e-11   1.80000e+00   1.71000e+00   1.89000e+00
| 7.57554e-11   1.80000e+00   1.71000e+00   1.89000e+00
| 7.80681e-11   1.80000e+00   1.71000e+00   1.89000e+00
| 7.93945e-11   1.80000e+00   1.71000e+00   1.89000e+00
| 8.55420e-11   1.80000e+00   1.71000e+00   1.89000e+00
| 9.55081e-11   1.80000e+00   1.71000e+00   1.89000e+00
| 9.79276e-11   1.80000e+00   1.71000e+00   1.89000e+00
| 1.07935e-10   1.80000e+00   1.71000e+00   1.89000e+00
| 1.13392e-10   1.80000e+00   1.71000e+00   1.89000e+00
| 1.17787e-10   1.80000e+00   1.71000e+00   1.89000e+00
| 1.27334e-10   1.80000e+00   1.71000e+00   1.89000e+00
| 1.31895e-10   1.80000e+00   1.71000e+00   1.89000e+00
| 1.39384e-10   1.80000e+00   1.71000e+00   1.89000e+00
| 1.47496e-10   1.80000e+00   1.71000e+00   1.89000e+00
| 1.52111e-10   1.80000e+00   1.71000e+00   1.89000e+00
| 1.61709e-10   1.80000e+00   1.71000e+00   1.89000e+00
| 1.73954e-10   1.80000e+00   1.71000e+00   1.89000e+00
| 1.78498e-10   1.80000e+00   1.71000e+00   1.89000e+00
| 1.89981e-10   1.80000e+00   1.71000e+00   1.89000e+00
| 2.00219e-10   1.80000e+00   1.71000e+00   1.89000e+00
| 2.06357e-10   1.80000e+00   1.71000e+00   1.89000e+00
| 2.12276e-10   1.80000e+00   1.71000e+00   1.89000e+00
| 2.22553e-10   1.80000e+00   1.71000e+00   1.89000e+00
| 2.29973e-10   1.80000e+00   1.71000e+00   1.89000e+00
| 2.35974e-10   1.80000e+00   1.71000e+00   1.89000e+00
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0s        1.8V       1.71V      1.89V
515.1ps   1.824V     1.711V     1.851V
736.8ps   1.804V     1.733V     1.695V
983.4ps   1.735V     1.725V     1.435V
1.324ns   1.521V     1.672V     1.047V
1.696ns   1.222V     1.516V     705.6mV
2.274ns   826.5mV    1.18V      460.5mV
2.926ns   602.1mV    874.1mV    405.2mV
3.804ns   524.4mV    680.8mV    393mV
7.037ns   505.9mV    609.5mV    390.8mV
[Rising Waveform]
R_fixture = 50
V_fixture = 0
C_fixture = 0.0p
| Time   typ   min   max
| 0.00000e+00   1.06221e-09   3.51730e-08   4.62084e-10
| 2.47507e-12   1.06262e-09   3.51733e-08   4.62544e-10
| 4.34525e-12   1.06297e-09   3.51737e-08   4.62918e-10
| 4.57959e-12   1.06302e-09   3.51737e-08   4.62965e-10
| 7.76228e-12   1.06362e-09   3.51742e-08   4.63531e-10
| 1.40250e-11   1.06419e-09   3.51751e-08   4.63671e-10
| 1.46859e-11   1.06418e-09   3.51750e-08   4.63682e-10
| 2.75535e-11   1.06272e-09   3.51745e-08   4.61326e-10
| 3.89156e-11   1.06029e-09   3.51724e-08   4.59728e-10
| 4.27651e-11   1.05946e-09   3.51717e-08   4.59288e-10
| 5.19470e-11   1.05748e-09   3.51688e-08   4.58146e-10
| 6.09735e-11   1.05341e-09   3.51645e-08   4.54584e-10
| 6.28654e-11   1.05185e-09   3.51634e-08   4.53687e-10
| 7.18355e-11   1.04369e-09   3.51528e-08   4.47390e-10
| 7.20853e-11   1.04338e-09   3.51523e-08   4.47170e-10
| 7.57553e-11   1.03831e-09   3.51448e-08   4.44028e-10
| 7.80681e-11   1.03592e-09   3.51395e-08   4.44157e-10
| 7.93944e-11   1.03458e-09   3.51384e-08   4.46073e-10
| 8.55418e-11   1.04944e-09   3.51450e-08   4.76463e-10
| 9.55024e-11   1.17117e-09   3.52153e-08   6.31198e-10
| 9.79222e-11   1.20281e-09   3.52569e-08   6.81506e-10
| 1.07935e-10   1.42899e-09   3.54497e-08   8.67366e-10
| 1.13390e-10   1.52707e-09   3.55708e-08   9.22073e-10
| 1.17787e-10   1.59288e-09   3.56684e-08   8.58885e-10
| 1.27331e-10   1.55172e-09   3.57540e-08   6.14860e-10
| 1.31897e-10   1.37655e-09   3.56523e-08   4.33425e-10
| 1.39387e-10   1.01695e-09   3.54726e-08   -2.63486e-11
| 1.47497e-10   3.51332e-10   3.48326e-08   -8.06363e-10
| 1.52118e-10   -3.47038e-10   3.42824e-08   -1.28616e-09
| 1.61717e-10   -1.83031e-09   3.27312e-08   -2.63668e-09
| 1.72749e-10   -3.64886e-09   3.06004e-08   -3.52481e-09
| 1.76286e-10   -3.80635e-09   2.99172e-08   -3.71295e-09
| 1.87607e-10   -3.95861e-09   2.89935e-08   -2.65527e-09
| 1.97419e-10   -2.98281e-09   2.92691e-08   -6.14912e-10
| 2.04005e-10   -1.83372e-09   2.97085e-08   7.74847e-10
| 2.10686e-10   -5.93699e-10   3.06165e-08   2.61543e-09
| 2.18675e-10   1.17854e-09   3.17023e-08   4.90311e-09
| 2.24324e-10   2.56422e-09   3.26176e-08   6.38446e-09
| 2.27448e-10   3.44851e-09   3.31381e-08   7.01126e-09
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0s        1.062nV    35.17nV    462.1pV
441.8ps   -11.32mV   60.13uV    12.89mV
936.7ps   40.47mV    -10.42mV   340mV
1.372ns   254.4mV    38.06mV    692.4mV
2.045ns   630.5mV    290.5mV    1.265V
2.495ns   897.1mV    471.7mV    1.451V
3.362ns   1.268V     828.4mV    1.527V
4.371ns   1.367V     1.129V     1.541V
5.33ns    1.388V     1.218V     1.544V
7.03ns    1.397V     1.255V     1.545V
[Falling Waveform]
R_fixture = 50
V_fixture = 0
C_fixture = 0.0p
| Time   typ   min   max
| 0.00000e+00   1.39821e+00   1.26477e+00   1.54491e+00
| 1.13297e-09   1.39821e+00   1.26477e+00   1.54489e+00
| 1.15654e-09   1.39821e+00   1.26477e+00   1.54487e+00
| 1.18242e-09   1.39821e+00   1.26477e+00   1.54484e+00
| 1.22296e-09   1.39821e+00   1.26477e+00   1.54479e+00
| 1.23788e-09   1.39821e+00   1.26477e+00   1.54484e+00
| 1.25874e-09   1.39821e+00   1.26477e+00   1.54503e+00
| 1.26949e-09   1.39821e+00   1.26477e+00   1.54519e+00
| 1.28893e-09   1.39821e+00   1.26477e+00   1.54579e+00
| 1.29819e-09   1.39821e+00   1.26477e+00   1.54635e+00
| 1.31333e-09   1.39821e+00   1.26477e+00   1.54725e+00
| 1.32057e-09   1.39820e+00   1.26477e+00   1.54749e+00
| 1.33426e-09   1.39820e+00   1.26477e+00   1.54718e+00
| 1.35139e-09   1.39819e+00   1.26477e+00   1.54444e+00
| 1.36230e-09   1.39819e+00   1.26477e+00   1.54054e+00
| 1.37421e-09   1.39818e+00   1.26477e+00   1.53378e+00
| 1.38957e-09   1.39817e+00   1.26477e+00   1.52050e+00
| 1.39866e-09   1.39816e+00   1.26477e+00   1.50896e+00
| 1.41871e-09   1.39813e+00   1.26477e+00   1.47299e+00
| 1.42342e-09   1.39813e+00   1.26477e+00   1.46284e+00
| 1.43897e-09   1.39811e+00   1.26477e+00   1.42898e+00
| 1.45242e-09   1.39810e+00   1.26477e+00   1.39997e+00
| 1.46803e-09   1.39811e+00   1.26477e+00   1.36552e+00
| 1.47838e-09   1.39812e+00   1.26477e+00   1.34281e+00
| 1.49672e-09   1.39820e+00   1.26477e+00   1.30397e+00
| 1.51166e-09   1.39833e+00   1.26477e+00   1.27374e+00
| 1.51678e-09   1.39840e+00   1.26477e+00   1.26369e+00
| 1.53257e-09   1.39863e+00   1.26476e+00   1.23310e+00
| 1.54907e-09   1.39908e+00   1.26476e+00   1.20201e+00
| 1.55943e-09   1.39951e+00   1.26476e+00   1.18291e+00
| 1.57328e-09   1.40012e+00   1.26475e+00   1.15783e+00
| 1.58481e-09   1.40051e+00   1.26475e+00   1.13730e+00
| 1.59751e-09   1.40056e+00   1.26474e+00   1.11486e+00
| 1.60704e-09   1.40019e+00   1.26473e+00   1.09844e+00
| 1.61973e-09   1.39881e+00   1.26472e+00   1.07658e+00
| 1.63644e-09   1.39509e+00   1.26471e+00   1.04857e+00
| 1.64492e-09   1.39205e+00   1.26470e+00   1.03436e+00
| 1.66448e-09   1.38177e+00   1.26468e+00   1.00258e+00
| 1.67583e-09   1.37268e+00   1.26467e+00   9.84141e-01
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0s        1.398V     1.265V     1.545V
314.5ps   1.373V     1.265V     984.1mV
606.2ps   900.3mV    1.239V     565mV
927ps     519.8mV    793.7mV    172.5mV
1.195ns   259.7mV    516.1mV    34.05mV
1.426ns   109.6mV    328.8mV    7.523mV
1.698ns   30.24mV    159mV      1.142mV
1.945ns   8.104mV    64.9mV     399.4uV
2.285ns   1.438mV    15.89mV    160.8uV
7.027ns   -785.7nV   239.2nV    -108.8nV
